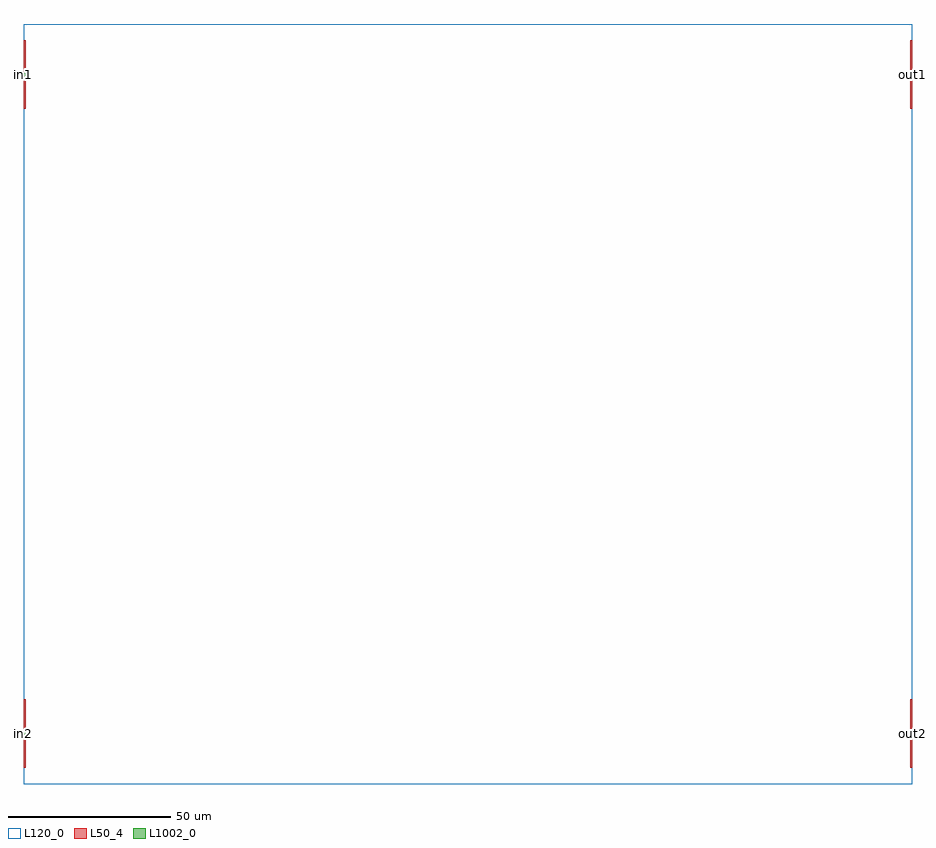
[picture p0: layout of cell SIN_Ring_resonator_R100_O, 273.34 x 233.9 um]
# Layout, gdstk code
import gdstk
lib = gdstk.Library(unit=1e-6, precision=1e-09)
def R(c, l, rs):  # rectangles x0, y0, x1, y1
    for r in rs: c.add(gdstk.rectangle(r[:2], r[2:], *l))
L50_4 = (50, 4)
L120_0 = (120, 0)
L1002_0 = (1002, 0)

sin_ring_resonator_r100_ = lib.new_cell('SIN_Ring_resonator_R100_O')
R(sin_ring_resonator_r100_, L50_4, [(0,5,0.5,15), (272.841,5,273.341,15), (0,16.1,0.5,26.1), (272.841,16.1,273.341,26.1), (0,207.8,0.5,217.8), (272.841,207.8,273.341,217.8), (0,218.9,0.5,228.9), (272.841,218.9,273.341,228.9)])
R(sin_ring_resonator_r100_, L120_0, [(0,0,273.341,233.9)])
R(sin_ring_resonator_r100_, L1002_0, [(0,15,0.5,16.1), (272.841,15,273.341,16.1), (0,217.8,0.5,218.9), (272.841,217.8,273.341,218.9)])
sin_ring_resonator_r100_.add(gdstk.Label('out2', (273.341,15.596), layer=1000, texttype=0))
sin_ring_resonator_r100_.add(gdstk.Label('out1', (273.341,218.424), layer=1000, texttype=0))
sin_ring_resonator_r100_.add(gdstk.Label('in2', (0,15.519), layer=1000, texttype=0))
sin_ring_resonator_r100_.add(gdstk.Label('in1', (0,218.334), layer=1000, texttype=0))

lib.write_gds('SIN_Ring_resonator_R100_O.gds')
